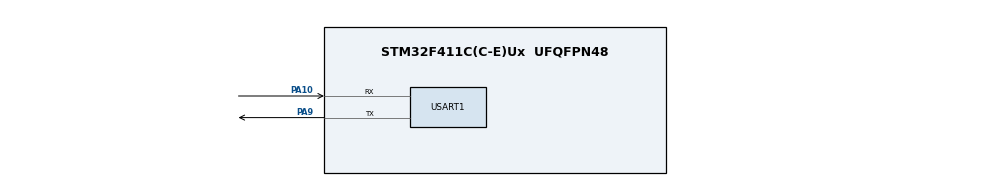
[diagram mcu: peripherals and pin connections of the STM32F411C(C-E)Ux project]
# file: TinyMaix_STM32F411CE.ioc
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Mcu.Family=STM32F4
Mcu.Name=STM32F411C(C-E)Ux
Mcu.Package=UFQFPN48
NVIC.PriorityGroup=NVIC_PRIORITYGROUP_4
PA10.Mode=Asynchronous
PA10.Signal=USART1_RX
PA9.Mode=Asynchronous
PA9.Signal=USART1_TX
PH0\ -\ OSC_IN.Mode=HSE-External-Oscillator
PH0\ -\ OSC_IN.Signal=RCC_OSC_IN
PH1\ -\ OSC_OUT.Mode=HSE-External-Oscillator
PH1\ -\ OSC_OUT.Signal=RCC_OSC_OUT
ProjectManager.HeapSize=0x200
ProjectManager.StackSize=0x400
ProjectManager.TargetToolchain=MDK-ARM V5.32
RCC.48MHZClocksFreq_Value=50000000
RCC.AHBFreq_Value=100000000
RCC.APB1CLKDivider=RCC_HCLK_DIV2
RCC.APB1Freq_Value=50000000
RCC.APB1TimFreq_Value=100000000
RCC.APB2Freq_Value=100000000
RCC.APB2TimFreq_Value=100000000
RCC.CortexFreq_Value=100000000
RCC.HCLKFreq_Value=100000000
RCC.HSE_VALUE=25000000
RCC.HSI_VALUE=16000000
RCC.LSE_VALUE=32768
RCC.PLLM=12
RCC.PLLN=96
RCC.PLLSourceVirtual=RCC_PLLSOURCE_HSE
RCC.SYSCLKFreq_VALUE=100000000
RCC.SYSCLKSource=RCC_SYSCLKSOURCE_PLLCLK
RCC.VCOOutputFreq_Value=200000000
USART1.VirtualMode=VM_ASYNC
board=custom

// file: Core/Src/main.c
/* USER CODE BEGIN Header */
/**
  ******************************************************************************
  * @file           : main.c
  * @brief          : Main program body
  ******************************************************************************
  * @attention
  *
  * Copyright (c) 2022 STMicroelectronics.
  * All rights reserved.
  *
  * This software is licensed under terms that can be found in the LICENSE file
  * in the root directory of this software component.
  * If no LICENSE file comes with this software, it is provided AS-IS.
  *
  ******************************************************************************
  */
/* USER CODE END Header */
#include "main.h"
#include <stdlib.h>
#include <stdio.h>
#include <stdarg.h>
#include "tinymaix.h"

UART_HandleTypeDef huart1;

void SystemClock_Config(void);
static void MX_GPIO_Init(void);
static void MX_USART1_UART_Init(void);

int fputc(int ch, FILE *f)
{
  HAL_UART_Transmit(&huart1, (uint8_t *)&ch, 1, 0xffff);
  return ch;
}

int fgetc(FILE *f)
{
  uint8_t ch = 0;
  HAL_UART_Receive(&huart1, &ch, 1, 0xffff);
  return ch;
}

#define TEST_MDL 2

#if TEST_MDL==0
	#include "mnist_q_valid.h"
	#define IMG_L   (28)
	#define IMG_CH  (1)
	#define CLASS_N (10)
#elif TEST_MDL==1
	#include "cifar10_q.h"
	#define IMG_L   (32)
	#define IMG_CH  (3)
	#define CLASS_N (10)
#else
	#include "mbnet96_0.25_q.h"
	#define IMG_L   (96)
	#define IMG_CH  (3)
	#define CLASS_N (1000)
#endif
//IMG_L*IMG_L*IMG_CH
uint8_t mnist_pic[128*128*3]={
  0,  0,  0,  0,  0,  0,  0,  0,  0,  0,  0,  0,  0,  0,  0,  0,  0,  0,  0,  0,  0,  0,  0,  0,  0,  0,  0,  0,
  0,  0,  0,  0,  0,  0,  0,  0,  0,  0,  0,  0,  0,  0,  0,  0,  0,  0,  0,  0,  0,  0,  0,  0,  0,  0,  0,  0,
  0,  0,  0,  0,  0,  0,  0,  0,  0,  0,  0,  0,  0,  0,  0,  0,  0,  0,  0,  0,  0,  0,  0,  0,  0,  0,  0,  0,
  0,  0,  0,  0,  0,  0,  0,  0,  0,  0,116,125,171,255,255,150, 93,  0,  0,  0,  0,  0,  0,  0,  0,  0,  0,  0,
  0,  0,  0,  0,  0,  0,  0,  0,  0,169,253,253,253,253,253,253,218, 30,  0,  0,  0,  0,  0,  0,  0,  0,  0,  0,
  0,  0,  0,  0,  0,  0,  0,  0,169,253,253,253,213,142,176,253,253,122,  0,  0,  0,  0,  0,  0,  0,  0,  0,  0,
  0,  0,  0,  0,  0,  0,  0, 52,250,253,210, 32, 12,  0,  6,206,253,140,  0,  0,  0,  0,  0,  0,  0,  0,  0,  0,
  0,  0,  0,  0,  0,  0,  0, 77,251,210, 25,  0,  0,  0,122,248,253, 65,  0,  0,  0,  0,  0,  0,  0,  0,  0,  0,
  0,  0,  0,  0,  0,  0,  0,  0, 31, 18,  0,  0,  0,  0,209,253,253, 65,  0,  0,  0,  0,  0,  0,  0,  0,  0,  0,
  0,  0,  0,  0,  0,  0,  0,  0,  0,  0,  0,  0,  0,117,247,253,198, 10,  0,  0,  0,  0,  0,  0,  0,  0,  0,  0,
  0,  0,  0,  0,  0,  0,  0,  0,  0,  0,  0,  0, 76,247,253,231, 63,  0,  0,  0,  0,  0,  0,  0,  0,  0,  0,  0,
  0,  0,  0,  0,  0,  0,  0,  0,  0,  0,  0,  0,128,253,253,144,  0,  0,  0,  0,  0,  0,  0,  0,  0,  0,  0,  0,
  0,  0,  0,  0,  0,  0,  0,  0,  0,  0,  0,176,246,253,159, 12,  0,  0,  0,  0,  0,  0,  0,  0,  0,  0,  0,  0,
  0,  0,  0,  0,  0,  0,  0,  0,  0,  0, 25,234,253,233, 35,  0,  0,  0,  0,  0,  0,  0,  0,  0,  0,  0,  0,  0,
  0,  0,  0,  0,  0,  0,  0,  0,  0,  0,198,253,253,141,  0,  0,  0,  0,  0,  0,  0,  0,  0,  0,  0,  0,  0,  0,
  0,  0,  0,  0,  0,  0,  0,  0,  0, 78,248,253,189, 12,  0,  0,  0,  0,  0,  0,  0,  0,  0,  0,  0,  0,  0,  0,
  0,  0,  0,  0,  0,  0,  0,  0, 19,200,253,253,141,  0,  0,  0,  0,  0,  0,  0,  0,  0,  0,  0,  0,  0,  0,  0,
  0,  0,  0,  0,  0,  0,  0,  0,134,253,253,173, 12,  0,  0,  0,  0,  0,  0,  0,  0,  0,  0,  0,  0,  0,  0,  0,
  0,  0,  0,  0,  0,  0,  0,  0,248,253,253, 25,  0,  0,  0,  0,  0,  0,  0,  0,  0,  0,  0,  0,  0,  0,  0,  0,
  0,  0,  0,  0,  0,  0,  0,  0,248,253,253, 43, 20, 20, 20, 20,  5,  0,  5, 20, 20, 37,150,150,150,147, 10,  0,
  0,  0,  0,  0,  0,  0,  0,  0,248,253,253,253,253,253,253,253,168,143,166,253,253,253,253,253,253,253,123,  0,
  0,  0,  0,  0,  0,  0,  0,  0,174,253,253,253,253,253,253,253,253,253,253,253,249,247,247,169,117,117, 57,  0,
  0,  0,  0,  0,  0,  0,  0,  0,  0,118,123,123,123,166,253,253,253,155,123,123, 41,  0,  0,  0,  0,  0,  0,  0,
  0,  0,  0,  0,  0,  0,  0,  0,  0,  0,  0,  0,  0,  0,  0,  0,  0,  0,  0,  0,  0,  0,  0,  0,  0,  0,  0,  0,
  0,  0,  0,  0,  0,  0,  0,  0,  0,  0,  0,  0,  0,  0,  0,  0,  0,  0,  0,  0,  0,  0,  0,  0,  0,  0,  0,  0,
  0,  0,  0,  0,  0,  0,  0,  0,  0,  0,  0,  0,  0,  0,  0,  0,  0,  0,  0,  0,  0,  0,  0,  0,  0,  0,  0,  0,
  0,  0,  0,  0,  0,  0,  0,  0,  0,  0,  0,  0,  0,  0,  0,  0,  0,  0,  0,  0,  0,  0,  0,  0,  0,  0,  0,  0,
  0,  0,  0,  0,  0,  0,  0,  0,  0,  0,  0,  0,  0,  0,  0,  0,  0,  0,  0,  0,  0,  0,  0,  0,  0,  0,  0,  0,
};

static uint32_t _t0,_t1;
static tm_err_t layer_cb(tm_mdl_t* mdl, tml_head_t* lh)
{   //dump middle result
    int h = lh->out_dims[1];
    int w = lh->out_dims[2];
    int ch= lh->out_dims[3];
    mtype_t* output = TML_GET_OUTPUT(mdl, lh);
    return TM_OK;
    _t1 = TM_GET_US();
    TM_PRINTF("===L%d use %.3f ms\n", mdl->layer_i, (float)(_t1-_t0)/1000.0);
    _t0 = TM_GET_US();
    TM_PRINTF("Layer %d callback ========\n", mdl->layer_i);
    #if 0
    for(int y=0; y<h; y++){
        TM_PRINTF("[");
        for(int x=0; x<w; x++){
            TM_PRINTF("[");
            for(int c=0; c<ch; c++){
            #if TM_MDL_TYPE == TM_MDL_FP32
                TM_PRINTF("%.3f,", output[(y*w+x)*ch+c]);
            #else
                TM_PRINTF("%.3f,", TML_DEQUANT(lh,output[(y*w+x)*ch+c]));
            #endif
            }
            TM_PRINTF("],");
        }
        TM_PRINTF("],\n");
    }
    TM_PRINTF("\n");
    #endif
    return TM_OK;
}

extern  __IO uint32_t uwTick;
static uint8_t mdl_buf[MDL_BUF_LEN];
//extern const char* labels[1000];
//extern const unsigned char pic[IMG_L*IMG_L*IMG_CH];

static void parse_output(tm_mat_t* outs)
{
    tm_mat_t out = outs[0];
    float* data  = out.dataf;
    float maxp = 0;
    int maxi = -1;
    for(int i=0; i<CLASS_N; i++){
        //TM_PRINTF("%3d: %.3f, ", i, data[i]); if(i%20==19)TM_PRINTF("\n");
        if(data[i] > maxp) {
            maxi = i;
            maxp = data[i];
        }
    }
    TM_PRINTF("### Predict output is: Class %d (), Prob %.3f\n", maxi, maxp);
		//TM_PRINTF("### Predict output is: Class %d (%s), Prob %.3f\n", maxi, labels[maxi], maxp);
    return;
}

int main(void)
{

  /* MCU Configuration--------------------------------------------------------*/

  /* Reset of all peripherals, Initializes the Flash interface and the Systick. */
  HAL_Init();

  /* Configure the system clock */
  SystemClock_Config();

  /* Initialize all configured peripherals */
  MX_GPIO_Init();
  MX_USART1_UART_Init();
  /* USER CODE BEGIN 2 */
	SysTick_Config(SystemCoreClock/1000);
	printf("Hello World! %.3f\r\n", 1.23456);

  /* USER CODE END 2 */
  printf("%d\r\n",uwTick);

	  TM_DBGT_INIT();
    TM_PRINTF("mnist demo\n");
    tm_mdl_t mdl;

    for(int i=0; i<28*28; i++){
        TM_PRINTF("%3d,", mnist_pic[i]);
        if(i%28==27)printf("\n");
    }

    tm_mat_t in_uint8 = {3,IMG_L,IMG_L,IMG_CH, (mtype_t*)mnist_pic};
    tm_mat_t in = {3,IMG_L,IMG_L,IMG_CH, NULL};
    tm_mat_t outs[1];
    tm_err_t res;
    tm_stat((tm_mdlbin_t*)mdl_data);

    res = tm_load(&mdl, mdl_data, mdl_buf, layer_cb, &in);
    if(res != TM_OK) {
        TM_PRINTF("tm model load err %d\n", res);
        return -1;
    }

#if TM_MDL_TYPE != TM_MDL_FP32
    res = tm_preprocess(&mdl, TMPP_UINT2INT, &in_uint8, &in);
#else
    res = tm_preprocess(&mdl, TMPP_UINT2FP01, &in_uint8, &in);
#endif
    TM_DBGT_START();
    res = tm_run(&mdl, &in, outs);
    TM_DBGT("tm_run");
    if(res==TM_OK) parse_output(outs);
    else TM_PRINTF("tm run error: %d\n", res);
    tm_unload(&mdl);

  /* Infinite loop */
  while (1)
  {

  }
}

void SystemClock_Config(void)
{
  RCC_OscInitTypeDef RCC_OscInitStruct = {0};
  RCC_ClkInitTypeDef RCC_ClkInitStruct = {0};

  /** Configure the main internal regulator output voltage
  */
  __HAL_RCC_PWR_CLK_ENABLE();
  __HAL_PWR_VOLTAGESCALING_CONFIG(PWR_REGULATOR_VOLTAGE_SCALE1);
  /** Initializes the RCC Oscillators according to the specified parameters
  * in the RCC_OscInitTypeDef structure.
  */
  RCC_OscInitStruct.OscillatorType = RCC_OSCILLATORTYPE_HSE;
  RCC_OscInitStruct.HSEState = RCC_HSE_ON;
  RCC_OscInitStruct.PLL.PLLState = RCC_PLL_ON;
  RCC_OscInitStruct.PLL.PLLSource = RCC_PLLSOURCE_HSE;
  RCC_OscInitStruct.PLL.PLLM = 8;  //12
  RCC_OscInitStruct.PLL.PLLN = 96 ;//96;
  RCC_OscInitStruct.PLL.PLLP = RCC_PLLP_DIV2;
  RCC_OscInitStruct.PLL.PLLQ = 4;
  if (HAL_RCC_OscConfig(&RCC_OscInitStruct) != HAL_OK)
  {
    Error_Handler();
  }
  /** Initializes the CPU, AHB and APB buses clocks
  */
  RCC_ClkInitStruct.ClockType = RCC_CLOCKTYPE_HCLK|RCC_CLOCKTYPE_SYSCLK
                              |RCC_CLOCKTYPE_PCLK1|RCC_CLOCKTYPE_PCLK2;
  RCC_ClkInitStruct.SYSCLKSource = RCC_SYSCLKSOURCE_PLLCLK;
  RCC_ClkInitStruct.AHBCLKDivider = RCC_SYSCLK_DIV1;
  RCC_ClkInitStruct.APB1CLKDivider = RCC_HCLK_DIV2;
  RCC_ClkInitStruct.APB2CLKDivider = RCC_HCLK_DIV1;

  if (HAL_RCC_ClockConfig(&RCC_ClkInitStruct, FLASH_LATENCY_3) != HAL_OK)
  {
    Error_Handler();
  }
}

static void MX_USART1_UART_Init(void)
{

  huart1.Instance = USART1;
  huart1.Init.BaudRate = 115200;
  huart1.Init.WordLength = UART_WORDLENGTH_8B;
  huart1.Init.StopBits = UART_STOPBITS_1;
  huart1.Init.Parity = UART_PARITY_NONE;
  huart1.Init.Mode = UART_MODE_TX_RX;
  huart1.Init.HwFlowCtl = UART_HWCONTROL_NONE;
  huart1.Init.OverSampling = UART_OVERSAMPLING_16;
  if (HAL_UART_Init(&huart1) != HAL_OK)
  {
    Error_Handler();
  }

}

static void MX_GPIO_Init(void)
{

  /* GPIO Ports Clock Enable */
  __HAL_RCC_GPIOH_CLK_ENABLE();
  __HAL_RCC_GPIOA_CLK_ENABLE();

}

void Error_Handler(void)
{
  __disable_irq();
  while (1)
  {
  }
}
